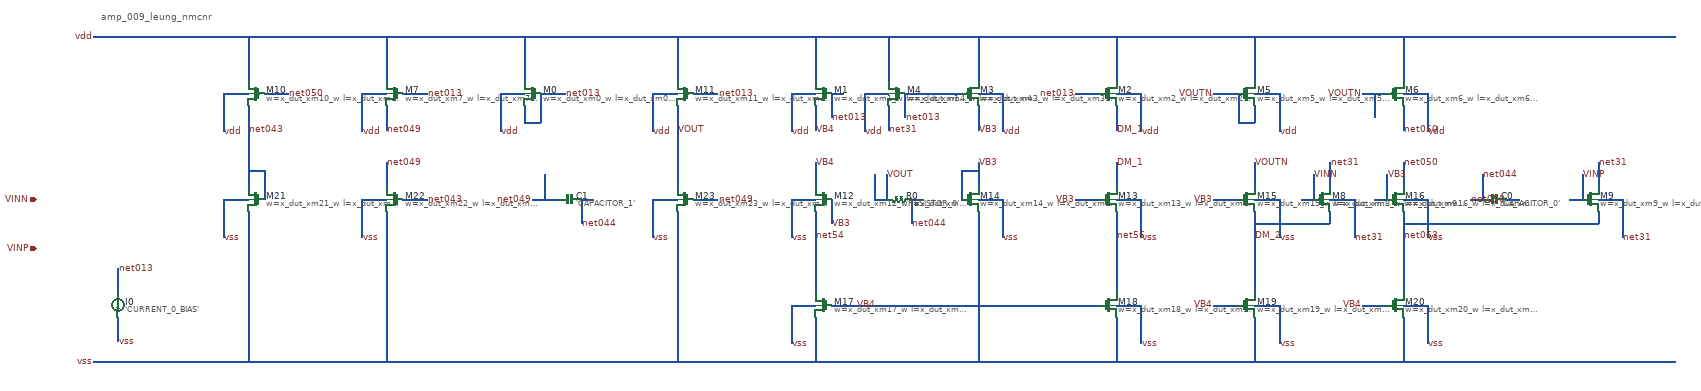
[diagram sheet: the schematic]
v {xschem version=3.4.6 file_version=1.2}
G {}
K {}
V {}
S {}
E {}
T {amp_009_leung_nmcnr} -1740 -200 0 0 0.4 0.4 {}
C {devices/capa_np.sym} 1685 260 1 0 {name=C0 value='CAPACITOR_0'}
C {devices/capa_np.sym} -590 260 1 0 {name=C1 value='CAPACITOR_1'}
C {devices/isource_np.sym} -1700 520 0 0 {name=I0 value='CURRENT_0_BIAS'}
C {devices/res_np.sym} 220 260 1 0 {name=R0 value='RESISTOR_0'}
C {devices/sg13_lv_pmos_np.sym} -680 0 0 1 {name=M0 model=sg13_lv_pmos spiceprefix=X w=x_dut_xm0_w l=x_dut_xm0_l m=x_dut_xm0_m}
C {devices/sg13_lv_pmos_np.sym} 35 0 0 1 {name=M1 model=sg13_lv_pmos spiceprefix=X w=x_dut_xm1_w l=x_dut_xm1_l m=x_dut_xm1_m}
C {devices/sg13_lv_pmos_np.sym} -1360 0 0 1 {name=M10 model=sg13_lv_pmos spiceprefix=X w=x_dut_xm10_w l=x_dut_xm10_l m=x_dut_xm10_m}
C {devices/sg13_lv_pmos_np.sym} -305 0 0 1 {name=M11 model=sg13_lv_pmos spiceprefix=X w=x_dut_xm11_w l=x_dut_xm11_l m=x_dut_xm11_m}
C {devices/sg13_lv_nmos_np.sym} 35 260 0 1 {name=M12 model=sg13_lv_nmos spiceprefix=X w=x_dut_xm12_w l=x_dut_xm12_l m=x_dut_xm12_m}
C {devices/sg13_lv_nmos_np.sym} 735 260 0 0 {name=M13 model=sg13_lv_nmos spiceprefix=X w=x_dut_xm13_w l=x_dut_xm13_l m=x_dut_xm13_m}
C {devices/sg13_lv_nmos_np.sym} 395 260 0 0 {name=M14 model=sg13_lv_nmos spiceprefix=X w=x_dut_xm14_w l=x_dut_xm14_l m=x_dut_xm14_m}
C {devices/sg13_lv_nmos_np.sym} 1075 260 0 0 {name=M15 model=sg13_lv_nmos spiceprefix=X w=x_dut_xm15_w l=x_dut_xm15_l m=x_dut_xm15_m}
C {devices/sg13_lv_nmos_np.sym} 1440 260 0 0 {name=M16 model=sg13_lv_nmos spiceprefix=X w=x_dut_xm16_w l=x_dut_xm16_l m=x_dut_xm16_m}
C {devices/sg13_lv_nmos_np.sym} 35 520 0 1 {name=M17 model=sg13_lv_nmos spiceprefix=X w=x_dut_xm17_w l=x_dut_xm17_l m=x_dut_xm17_m}
C {devices/sg13_lv_nmos_np.sym} 735 520 0 0 {name=M18 model=sg13_lv_nmos spiceprefix=X w=x_dut_xm18_w l=x_dut_xm18_l m=x_dut_xm18_m}
C {devices/sg13_lv_nmos_np.sym} 1075 520 0 0 {name=M19 model=sg13_lv_nmos spiceprefix=X w=x_dut_xm19_w l=x_dut_xm19_l m=x_dut_xm19_m}
C {devices/sg13_lv_pmos_np.sym} 735 0 0 0 {name=M2 model=sg13_lv_pmos spiceprefix=X w=x_dut_xm2_w l=x_dut_xm2_l m=x_dut_xm2_m}
C {devices/sg13_lv_nmos_np.sym} 1440 520 0 0 {name=M20 model=sg13_lv_nmos spiceprefix=X w=x_dut_xm20_w l=x_dut_xm20_l m=x_dut_xm20_m}
C {devices/sg13_lv_nmos_np.sym} -1360 260 0 1 {name=M21 model=sg13_lv_nmos spiceprefix=X w=x_dut_xm21_w l=x_dut_xm21_l m=x_dut_xm21_m}
C {devices/sg13_lv_nmos_np.sym} -1020 260 0 1 {name=M22 model=sg13_lv_nmos spiceprefix=X w=x_dut_xm22_w l=x_dut_xm22_l m=x_dut_xm22_m}
C {devices/sg13_lv_nmos_np.sym} -305 260 0 1 {name=M23 model=sg13_lv_nmos spiceprefix=X w=x_dut_xm23_w l=x_dut_xm23_l m=x_dut_xm23_m}
C {devices/sg13_lv_pmos_np.sym} 395 0 0 0 {name=M3 model=sg13_lv_pmos spiceprefix=X w=x_dut_xm3_w l=x_dut_xm3_l m=x_dut_xm3_m}
C {devices/sg13_lv_pmos_np.sym} 215 0 0 1 {name=M4 model=sg13_lv_pmos spiceprefix=X w=x_dut_xm4_w l=x_dut_xm4_l m=x_dut_xm4_m}
C {devices/sg13_lv_pmos_np.sym} 1075 0 0 0 {name=M5 model=sg13_lv_pmos spiceprefix=X w=x_dut_xm5_w l=x_dut_xm5_l m=x_dut_xm5_m}
C {devices/sg13_lv_pmos_np.sym} 1440 0 0 0 {name=M6 model=sg13_lv_pmos spiceprefix=X w=x_dut_xm6_w l=x_dut_xm6_l m=x_dut_xm6_m}
C {devices/sg13_lv_pmos_np.sym} -1020 0 0 1 {name=M7 model=sg13_lv_pmos spiceprefix=X w=x_dut_xm7_w l=x_dut_xm7_l m=x_dut_xm7_m}
C {devices/sg13_lv_pmos_np.sym} 1260 260 0 0 {name=M8 model=sg13_lv_pmos spiceprefix=X w=x_dut_xm8_w l=x_dut_xm8_l m=x_dut_xm8_m}
C {devices/sg13_lv_pmos_np.sym} 1920 260 0 0 {name=M9 model=sg13_lv_pmos spiceprefix=X w=x_dut_xm9_w l=x_dut_xm9_l m=x_dut_xm9_m}
N -1700 430 -1700 490 {}
N -1700 550 -1700 610 {}
N -1440 0 -1440 94 {}
N -1440 260 -1440 354 {}
N -1380 -140 -1380 -30 {}
N -1380 30 -1380 230 {}
N -1380 290 -1380 660 {}
N -1340 190 -1340 260 {}
N -1100 0 -1100 94 {}
N -1100 260 -1100 354 {}
N -1040 -140 -1040 -30 {}
N -1040 30 -1040 90 {}
N -1040 170 -1040 230 {}
N -1040 290 -1040 660 {}
N -760 0 -760 94 {}
N -700 -140 -700 -30 {}
N -700 30 -700 70 {}
N -660 0 -660 70 {}
N -650 200 -650 260 {}
N -560 260 -560 320 {}
N -385 0 -385 94 {}
N -385 260 -385 354 {}
N -325 -140 -325 -30 {}
N -325 30 -325 230 {}
N -325 290 -325 660 {}
N -45 0 -45 94 {}
N -45 260 -45 354 {}
N -45 520 -45 614 {}
N 15 -140 15 -30 {}
N 15 30 15 90 {}
N 15 170 15 230 {}
N 15 290 15 490 {}
N 15 550 15 660 {}
N 55 0 55 60 {}
N 55 260 55 320 {}
N 135 0 135 94 {}
N 160 200 160 260 {}
N 190 200 190 260 {}
N 195 -140 195 -30 {}
N 195 30 195 90 {}
N 235 0 235 60 {}
N 250 260 250 320 {}
N 375 190 375 260 {}
N 415 -140 415 -30 {}
N 415 30 415 90 {}
N 415 170 415 230 {}
N 415 290 415 660 {}
N 475 0 475 94 {}
N 475 260 475 354 {}
N 755 -140 755 -30 {}
N 755 30 755 90 {}
N 755 170 755 230 {}
N 755 290 755 490 {}
N 755 550 755 660 {}
N 815 0 815 94 {}
N 815 260 815 354 {}
N 815 520 815 614 {}
N 1055 0 1055 70 {}
N 1095 -140 1095 -30 {}
N 1095 30 1095 70 {}
N 1095 170 1095 230 {}
N 1095 290 1095 490 {}
N 1095 550 1095 660 {}
N 1155 0 1155 94 {}
N 1155 260 1155 354 {}
N 1155 520 1155 614 {}
N 1240 200 1240 260 {}
N 1280 170 1280 230 {}
N 1280 290 1280 320 {}
N 1340 260 1340 354 {}
N 1390 0 1390 60 {}
N 1420 200 1420 260 {}
N 1460 -140 1460 -30 {}
N 1460 30 1460 90 {}
N 1460 170 1460 230 {}
N 1460 290 1460 490 {}
N 1460 550 1460 660 {}
N 1520 0 1520 94 {}
N 1520 260 1520 354 {}
N 1520 520 1520 614 {}
N 1655 200 1655 260 {}
N 1900 200 1900 260 {}
N 1940 170 1940 230 {}
N 1940 290 1940 320 {}
N 2000 260 2000 354 {}
N -1760 -140 2130 -140 {}
N -1440 0 -1380 0 {}
N -1340 0 -1280 0 {}
N -1100 0 -1040 0 {}
N -1000 0 -940 0 {}
N -760 0 -700 0 {}
N -660 0 -600 0 {}
N -385 0 -325 0 {}
N -285 0 -225 0 {}
N -45 0 15 0 {}
N 55 0 85 0 {}
N 135 0 195 0 {}
N 235 0 375 0 {}
N 415 0 475 0 {}
N 655 0 715 0 {}
N 755 0 815 0 {}
N 995 0 1055 0 {}
N 1095 0 1155 0 {}
N 1360 0 1420 0 {}
N 1460 0 1520 0 {}
N -700 70 -660 70 {}
N 1055 70 1095 70 {}
N -1380 190 -1340 190 {}
N 375 190 415 190 {}
N -1440 260 -1380 260 {}
N -1100 260 -1040 260 {}
N -1000 260 -940 260 {}
N -680 260 -620 260 {}
N -560 260 -530 260 {}
N -385 260 -325 260 {}
N -285 260 -225 260 {}
N -45 260 15 260 {}
N 160 260 190 260 {}
N 250 260 280 260 {}
N 415 260 475 260 {}
N 655 260 715 260 {}
N 755 260 815 260 {}
N 995 260 1055 260 {}
N 1095 260 1155 260 {}
N 1210 260 1240 260 {}
N 1280 260 1340 260 {}
N 1390 260 1420 260 {}
N 1460 260 1520 260 {}
N 1625 260 1655 260 {}
N 1715 260 1745 260 {}
N 1870 260 1900 260 {}
N 1940 260 2000 260 {}
N 1095 320 1280 320 {}
N 1460 320 1940 320 {}
N -45 520 15 520 {}
N 55 520 715 520 {}
N 755 520 815 520 {}
N 995 520 1055 520 {}
N 1095 520 1155 520 {}
N 1360 520 1420 520 {}
N 1460 520 1520 520 {}
N -1760 660 2130 660 {}
C {devices/lab_wire.sym} -1760 -140 0 0 {name=l0 lab=vdd}
C {devices/lab_wire.sym} -1760 660 0 0 {name=l1 lab=vss}
C {devices/lab_wire.sym} 755 90 2 0 {name=l2 lab=DM_1}
C {devices/lab_wire.sym} 755 170 0 1 {name=l3 lab=DM_1}
C {devices/lab_wire.sym} 1095 350 2 0 {name=l4 lab=DM_2}
C {devices/lab_wire.sym} 55 320 2 0 {name=l5 lab=VB3}
C {devices/lab_wire.sym} 415 170 0 1 {name=l6 lab=VB3}
C {devices/lab_wire.sym} 415 90 2 0 {name=l7 lab=VB3}
C {devices/lab_wire.sym} 655 260 0 0 {name=l8 lab=VB3}
C {devices/lab_wire.sym} 995 260 0 0 {name=l9 lab=VB3}
C {devices/lab_wire.sym} 1420 200 0 1 {name=l10 lab=VB3}
C {devices/lab_wire.sym} 15 90 2 0 {name=l11 lab=VB4}
C {devices/lab_wire.sym} 15 170 0 1 {name=l12 lab=VB4}
C {devices/lab_wire.sym} 115 520 0 1 {name=l13 lab=VB4}
C {devices/lab_wire.sym} 995 520 0 0 {name=l14 lab=VB4}
C {devices/lab_wire.sym} 1360 520 0 0 {name=l15 lab=VB4}
C {devices/lab_wire.sym} 1240 200 0 1 {name=l16 lab=VINN}
C {devices/lab_wire.sym} 1900 200 0 1 {name=l17 lab=VINP}
C {devices/lab_wire.sym} -325 90 2 0 {name=l18 lab=VOUT}
C {devices/lab_wire.sym} 190 200 0 1 {name=l19 lab=VOUT}
C {devices/lab_wire.sym} 995 0 0 0 {name=l20 lab=VOUTN}
C {devices/lab_wire.sym} 1095 170 0 1 {name=l21 lab=VOUTN}
C {devices/lab_wire.sym} 1360 0 0 0 {name=l22 lab=VOUTN}
C {devices/lab_wire.sym} -940 0 0 1 {name=l23 lab=net013}
C {devices/lab_wire.sym} -600 0 0 1 {name=l24 lab=net013}
C {devices/lab_wire.sym} -225 0 0 1 {name=l25 lab=net013}
C {devices/lab_wire.sym} 55 60 2 0 {name=l26 lab=net013}
C {devices/lab_wire.sym} 235 60 2 0 {name=l27 lab=net013}
C {devices/lab_wire.sym} 655 0 0 0 {name=l28 lab=net013}
C {devices/lab_wire.sym} -1380 90 2 0 {name=l29 lab=net043}
C {devices/lab_wire.sym} -940 260 0 1 {name=l30 lab=net043}
C {devices/lab_wire.sym} -560 320 2 0 {name=l31 lab=net044}
C {devices/lab_wire.sym} 250 320 2 0 {name=l32 lab=net044}
C {devices/lab_wire.sym} 1655 200 0 1 {name=l33 lab=net044}
C {devices/lab_wire.sym} -1040 90 2 0 {name=l34 lab=net049}
C {devices/lab_wire.sym} -1040 170 0 1 {name=l35 lab=net049}
C {devices/lab_wire.sym} -680 260 0 0 {name=l36 lab=net049}
C {devices/lab_wire.sym} -225 260 0 1 {name=l37 lab=net049}
C {devices/lab_wire.sym} -1280 0 0 1 {name=l38 lab=net050}
C {devices/lab_wire.sym} 1460 90 2 0 {name=l39 lab=net050}
C {devices/lab_wire.sym} 1460 170 0 1 {name=l40 lab=net050}
C {devices/lab_wire.sym} 1715 260 0 0 {name=l41 lab=net050}
C {devices/lab_wire.sym} 1460 350 2 0 {name=l42 lab=net063}
C {devices/lab_wire.sym} 195 90 2 0 {name=l43 lab=net31}
C {devices/lab_wire.sym} 1280 170 0 1 {name=l44 lab=net31}
C {devices/lab_wire.sym} 1940 170 0 1 {name=l45 lab=net31}
C {devices/lab_wire.sym} 15 350 2 0 {name=l46 lab=net54}
C {devices/lab_wire.sym} 755 350 2 0 {name=l47 lab=net56}
C {devices/lab_wire.sym} 1340 354 2 0 {name=l48 lab=net31}
C {devices/lab_wire.sym} 2000 354 2 0 {name=l49 lab=net31}
C {devices/lab_wire.sym} -760 94 2 0 {name=l50 lab=vdd}
C {devices/lab_wire.sym} -45 94 2 0 {name=l51 lab=vdd}
C {devices/lab_wire.sym} -1440 94 2 0 {name=l52 lab=vdd}
C {devices/lab_wire.sym} -385 94 2 0 {name=l53 lab=vdd}
C {devices/lab_wire.sym} 815 94 2 0 {name=l54 lab=vdd}
C {devices/lab_wire.sym} 475 94 2 0 {name=l55 lab=vdd}
C {devices/lab_wire.sym} 135 94 2 0 {name=l56 lab=vdd}
C {devices/lab_wire.sym} 1155 94 2 0 {name=l57 lab=vdd}
C {devices/lab_wire.sym} 1520 94 2 0 {name=l58 lab=vdd}
C {devices/lab_wire.sym} -1100 94 2 0 {name=l59 lab=vdd}
C {devices/lab_wire.sym} -45 354 2 0 {name=l60 lab=vss}
C {devices/lab_wire.sym} 815 354 2 0 {name=l61 lab=vss}
C {devices/lab_wire.sym} 475 354 2 0 {name=l62 lab=vss}
C {devices/lab_wire.sym} 1155 354 2 0 {name=l63 lab=vss}
C {devices/lab_wire.sym} 1520 354 2 0 {name=l64 lab=vss}
C {devices/lab_wire.sym} -45 614 2 0 {name=l65 lab=vss}
C {devices/lab_wire.sym} 815 614 2 0 {name=l66 lab=vss}
C {devices/lab_wire.sym} 1155 614 2 0 {name=l67 lab=vss}
C {devices/lab_wire.sym} 1520 614 2 0 {name=l68 lab=vss}
C {devices/lab_wire.sym} -1440 354 2 0 {name=l69 lab=vss}
C {devices/lab_wire.sym} -1100 354 2 0 {name=l70 lab=vss}
C {devices/lab_wire.sym} -385 354 2 0 {name=l71 lab=vss}
C {devices/lab_wire.sym} -1700 430 0 1 {name=l72 lab=net013}
C {devices/lab_wire.sym} -1700 610 2 0 {name=l73 lab=vss}
C {devices/ipin.sym} -1900 260 0 0 {name=p0 lab=VINN}
C {devices/ipin.sym} -1900 380 0 0 {name=p1 lab=VINP}
